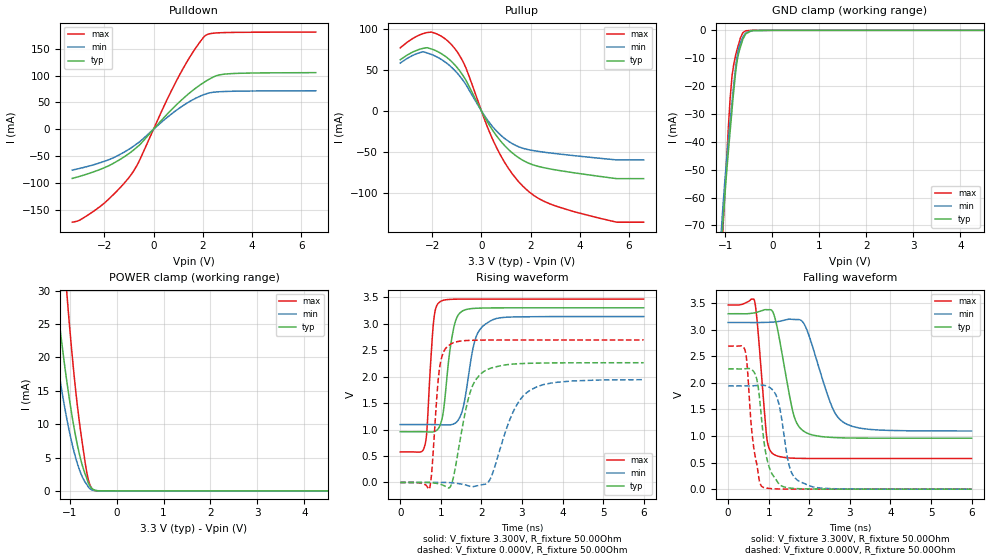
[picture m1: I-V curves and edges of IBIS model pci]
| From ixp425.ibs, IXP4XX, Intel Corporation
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[Model]   pci
Model_type   I/O
Vinl = 800.000mV
Vinh = 2.000V
Vmeas = 1.500V
Cref = 0.000F
|   typ   min   max
C_comp   3.000pF   2.700pF   3.300pF
[Voltage Range]   3.300V   3.135V   3.465V
[Temperature Range]   25.0   110.0   -40.0
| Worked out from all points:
|   slope of the pulldown table from 0 to 0.495 V, typ, clamps not added: 19.6 ohm
|   slope of the pullup table from 0 to 0.495 V, typ, clamps not added: 19.5 ohm
|   GND clamp passes 1 mA (typ) near -0.54 V on its own axis
|   POWER clamp passes 1 mA (typ) near -0.59 V on its own axis
|   falling waveform, V_fixture 3.300V, R_fixture 50.00Ohm: 20-80 % time 343ps typ, 524ps min, 182ps max; typ from 3.3 V to 0.958 V
|   rising waveform, V_fixture 3.300V, R_fixture 50.00Ohm: 20-80 % time 219ps typ, 284ps min, 133ps max; typ from 0.958 V to 3.3 V
|   rising waveform, V_fixture 0.000V, R_fixture 50.00Ohm: 20-80 % time 376ps typ, 580ps min, 158ps max; typ from 0 V to 2.26 V
|   falling waveform, V_fixture 0.000V, R_fixture 50.00Ohm: 20-80 % time 237ps typ, 262ps min, 202ps max; typ from 2.26 V to 0 V
[Pulldown]
|   Voltage   I(typ)   I(min)   I(max)
-3.3V     -91.81mA   -76.25mA   -173.6mA
-2.995V   -87.89mA   -73.11mA   -169.6mA
-2V       -71.83mA   -59.94mA   -138.1mA
-900mV    -42.1mA    -34.42mA   -84.13mA
-600mV    -30.71mA   -24.64mA   -61.1mA
370mV     19.06mA    15.05mA    37.7mA
1.045V    50.61mA    39.26mA    100.2mA
1.59V     72.39mA    54.94mA    143.1mA
2.08V     88.46mA    65.23mA    174mA
2.545V    99.84mA    69.65mA    179.9mA
2.89V     103mA      70.56mA    180.6mA
6.595V    105.8mA    71.9mA     181.5mA
[GND Clamp]
|   Voltage   I(typ)   I(min)   I(max)
-3.3V     -1.837A    -1.782A    -2.142A
-1.1V     -82.16mA   -75.28mA   -89.43mA
-1.06V    -71.18mA   -65.17mA   -74.61mA
-1.045V   -67.36mA   -61.57mA   -69.22mA
-930mV    -42.2mA    -38.29mA   -33.02mA
-860mV    -28.79mA   -26.06mA   -16.73mA
-785mV    -15.48mA   -13.65mA   -9.2mA
-745mV    -10.52mA   -8.798mA   -6.545mA
-680mV    -6.029mA   -4.579mA   -2.739mA
-575mV    -1.514mA   -1.11mA    -221.4uA
0V        -56.89nA   -17.57nA   -32.79pA
6.595V    0A         0A         0A
[Pullup]
|   Voltage   I(typ)   I(min)   I(max)
-3.3V     62.29mA    58.22mA    76.79mA
-2.46V    75.48mA    71.27mA    93.15mA
-2.035V   75.44mA    68.76mA    95.98mA
-1.185V   59.23mA    52.26mA    79.63mA
-670mV    39.32mA    33.81mA    55mA
235mV     -13mA      -10.7mA    -18.96mA
790mV     -37.09mA   -29.71mA   -54.75mA
1.41V     -54.88mA   -42.36mA   -82.66mA
2.11V     -65.9mA    -48.4mA    -102.6mA
3.045V    -72.1mA    -52.2mA    -116.2mA
4.7V      -79.4mA    -57.42mA   -130mA
6.595V    -82.58mA   -59.77mA   -135.6mA
[POWER Clamp]
|   Voltage   I(typ)   I(min)   I(max)
-3.3V     221.1mA    178.3mA    345.2mA
-1.46V    41.39mA    29.65mA    71.72mA
-1.43V    39.23mA    27.98mA    68.17mA
-1.325V   32.02mA    22.46mA    56.21mA
-1.26V    27.84mA    19.29mA    49.19mA
-1.06V    16.51mA    10.87mA    29.8mA
-895mV    9.118mA    5.612mA    16.77mA
-785mV    5.35mA     3.076mA    10.01mA
-635mV    1.89mA     986.6uA    2.845mA
-535mV    440.6uA    188.8uA    455.2uA
-390mV    28.44uA    11.22uA    8.083uA
6.595V    0A         0A         0A
[Ramp]
R_load = 50.00Ohm
|   typ   min   max
dV/dt_r   1.357V/375.181ps   1.165V/579.390ps   1.615V/158.446ps
dV/dt_f   1.405V/342.580ps   1.225V/523.955ps   1.733V/181.950ps
[Falling Waveform]
V_fixture = 3.300V
V_fixture_min = 3.135V
V_fixture_max = 3.465V
R_fixture = 50.00Ohm
|   Time   V(typ)   V(min)   V(max)
0s        3.3V       3.135V     3.465V
650ps     3.317V     3.134V     3.542V
720ps     3.331V     3.134V     3.114V
950ps     3.376V     3.138V     982.6mV
1.13ns    3.279V     3.144V     651.8mV
1.61ns    1.411V     3.193V     582.4mV
1.89ns    1.077V     3.082V     578.1mV
2.54ns    974.4mV    1.586V     576.7mV
2.83ns    964.9mV    1.264V     576.6mV
6ns       958.5mV    1.094V     576.5mV
[Rising Waveform]
V_fixture = 3.300V
V_fixture_min = 3.135V
V_fixture_max = 3.465V
R_fixture = 50.00Ohm
|   Time   V(typ)   V(min)   V(max)
0s        958.5mV    1.094V     576.5mV
610ps     956.7mV    1.094V     709mV
660ps     955.2mV    1.095V     1.011V
820ps     957.2mV    1.094V     3.023V
990ps     1.099V     1.09V      3.42V
1.31ns    2.889V     1.103V     3.461V
1.53ns    3.237V     1.357V     3.464V
1.86ns    3.291V     2.73V      3.465V
2.28ns    3.298V     3.075V     3.465V
6ns       3.3V       3.135V     3.465V
[Rising Waveform]
V_fixture = 0.000V
V_fixture_min = 0.000V
V_fixture_max = 0.000V
R_fixture = 50.00Ohm
|   Time   V(typ)   V(min)   V(max)
0s        782.3nV    285.7nV    1.747nV
720ps     -976.7uV   178.1uV    -115mV
970ps     -29.9mV    773.6uV    2.168V
1.25ns    -59.19mV   -5.463mV   2.617V
1.69ns    1.615V     -66.83mV   2.684V
2.06ns    2.097V     -37.48mV   2.69V
2.26ns    2.166V     140.6mV    2.691V
2.78ns    2.236V     1.328V     2.692V
3.18ns    2.251V     1.73V      2.692V
6ns       2.262V     1.942V     2.692V
[Falling Waveform]
V_fixture = 0.000V
V_fixture_min = 0.000V
V_fixture_max = 0.000V
R_fixture = 50.00Ohm
|   Time   V(typ)   V(min)   V(max)
0s        2.262V     1.942V     2.692V
420ps     2.265V     1.942V     2.6V
620ps     2.221V     1.944V     841.9mV
730ps     1.972V     1.952V     354.2mV
850ps     1.118V     1.956V     40.47mV
1.08ns    288.5mV    1.879V     8.799mV
1.26ns    94.52mV    1.569V     3.397mV
1.51ns    22.88mV    427.2mV    1.167mV
1.77ns    8.151mV    140mV      481.7uV
6ns       782.3nV    285.7nV    1.747nV
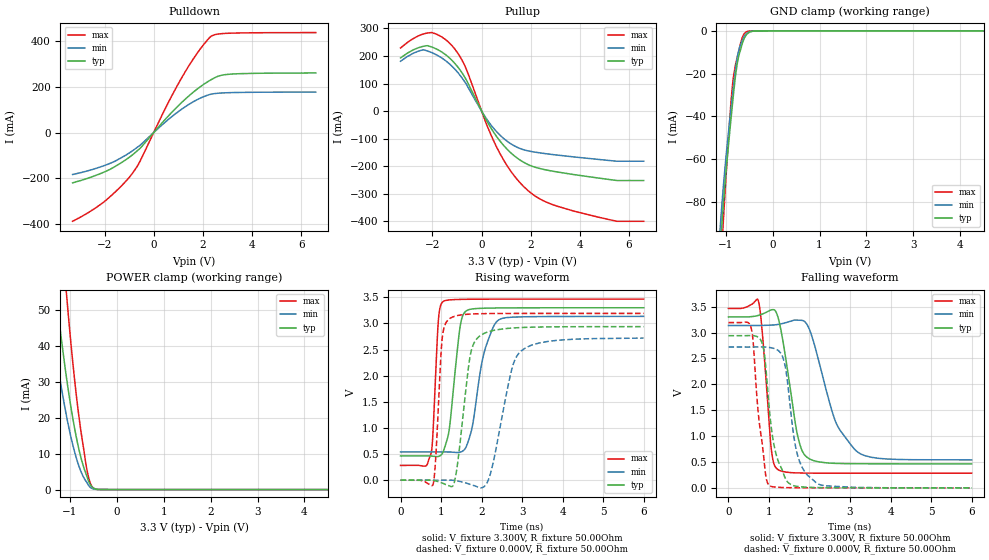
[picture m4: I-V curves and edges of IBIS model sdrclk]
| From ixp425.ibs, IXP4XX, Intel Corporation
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[Model]   sdrclk
Model_type   I/O
Vinl = 800.000mV
Vinh = 2.000V
Vmeas = 1.500V
Cref = 0.000F
|   typ   min   max
C_comp   3.000pF   2.700pF   3.300pF
[Voltage Range]   3.300V   3.135V   3.465V
[Temperature Range]   25.0   110.0   -40.0
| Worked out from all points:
|   slope of the pulldown table from 0 to 0.495 V, typ, clamps not added: 8.2 ohm
|   slope of the pullup table from 0 to 0.495 V, typ, clamps not added: 6.39 ohm
|   GND clamp passes 1 mA (typ) near -0.51 V on its own axis
|   POWER clamp passes 1 mA (typ) near -0.54 V on its own axis
|   falling waveform, V_fixture 3.300V, R_fixture 50.00Ohm: 20-80 % time 335ps typ, 631ps min, 182ps max; typ from 3.3 V to 0.464 V
|   rising waveform, V_fixture 3.300V, R_fixture 50.00Ohm: 20-80 % time 224ps typ, 353ps min, 114ps max; typ from 0.464 V to 3.3 V
|   rising waveform, V_fixture 0.000V, R_fixture 50.00Ohm: 20-80 % time 262ps typ, 422ps min, 126ps max; typ from 0 V to 2.94 V
|   falling waveform, V_fixture 0.000V, R_fixture 50.00Ohm: 20-80 % time 279ps typ, 304ps min, 231ps max; typ from 2.94 V to 0 V
[Pulldown]
|   Voltage   I(typ)   I(min)   I(max)
-3.3V     -219mA     -182.8mA   -386.5mA
-2.07V    -174.3mA   -146.1mA   -305.9mA
-1.35V    -133.5mA   -111.6mA   -236.4mA
-865mV    -97.09mA   -79.63mA   -177.4mA
-590mV    -72.25mA   -58.19mA   -131.8mA
495mV     60.39mA    47.75mA    109.6mA
1.11V     128.1mA    99.6mA     233.2mA
1.73V     186.1mA    141.1mA    339.5mA
2.3V      228mA      166.3mA    416.3mA
2.645V    246.3mA    171.5mA    429.5mA
3.12V     254.4mA    173.9mA    432.9mA
6.595V    259.6mA    176.5mA    435.6mA
[GND Clamp]
|   Voltage   I(typ)   I(min)   I(max)
-3.3V     -1.926A    -1.857A    -2.229A
-1.11V    -99.68mA   -89.97mA   -113.7mA
-1.065V   -85.71mA   -77.06mA   -94.89mA
-1.045V   -79.88mA   -71.62mA   -87.17mA
-890mV    -42.05mA   -37.16mA   -34.22mA
-840mV    -31.08mA   -27.22mA   -22.58mA
-785mV    -20.1mA    -17.16mA   -15.29mA
-740mV    -13.67mA   -10.94mA   -11.14mA
-645mV    -5.889mA   -4.486mA   -3.1mA
-550mV    -1.607mA   -1.138mA   -370.4uA
0V        -99.35nA   -30.05nA   -3.864nA
6.595V    0A         0A         0A
[Pullup]
|   Voltage   I(typ)   I(min)   I(max)
-3.3V     193mA      180.8mA    229.1mA
-2.47V    232.9mA    220.3mA    276.8mA
-2.035V   232.7mA    212.5mA    285mA
-1.185V   182.2mA    161mA      235.4mA
-685mV    123mA      106mA      164.9mA
240mV     -40.44mA   -33.33mA   -56.56mA
795mV     -113.9mA   -91.35mA   -161.8mA
1.415V    -168.4mA   -130mA     -244.7mA
2.12V     -202.3mA   -148.3mA   -304.8mA
3.035V    -220.4mA   -159.3mA   -344.1mA
4.69V     -242.3mA   -174.9mA   -383.7mA
6.595V    -252mA     -182.1mA   -400.1mA
[POWER Clamp]
|   Voltage   I(typ)   I(min)   I(max)
-3.3V     403.8mA    324.6mA    607.2mA
-1.51V    81.8mA     58.73mA    136mA
-1.45V    73.79mA    52.55mA    123.4mA
-1.275V   52.29mA    36.16mA    89.09mA
-1.095V   33.38mA    22.11mA    58.17mA
-1.06V    30.12mA    19.74mA    52.74mA
-920mV    18.6mA     11.56mA    33.24mA
-770mV    9.234mA    5.265mA    16.86mA
-635mV    3.649mA    1.937mA    5.465mA
-530mV    782.2uA    338.8uA    898uA
-390mV    54.09uA    21.66uA    23.63uA
6.595V    0A         0A         0A
[Ramp]
R_load = 50.00Ohm
|   typ   min   max
dV/dt_r   1.763V/261.419ps   1.632V/421.770ps   1.915V/125.723ps
dV/dt_f   1.702V/333.826ps   1.557V/629.863ps   1.909V/181.980ps
[Falling Waveform]
V_fixture = 3.300V
V_fixture_min = 3.135V
V_fixture_max = 3.465V
R_fixture = 50.00Ohm
|   Time   V(typ)   V(min)   V(max)
0s        3.3V       3.135V     3.465V
740ps     3.331V     3.135V     3.607V
840ps     3.358V     3.136V     2.961V
1.06ns    3.437V     3.143V     731.4mV
1.22ns    3.302V     3.155V     354.6mV
1.71ns    996.4mV    3.238V     288.5mV
1.95ns    584.5mV    3.141V     284.8mV
2.65ns    472.7mV    1.266V     283mV
3.15ns    466mV      716.6mV    283mV
6ns       463.8mV    540.5mV    283mV
[Rising Waveform]
V_fixture = 3.300V
V_fixture_min = 3.135V
V_fixture_max = 3.465V
R_fixture = 50.00Ohm
|   Time   V(typ)   V(min)   V(max)
0s        463.8mV    540.5mV    283mV
750ps     463.2mV    540.7mV    504.2mV
940ps     455.9mV    541.2mV    3.11V
1.06ns    560mV      541mV      3.423V
1.21ns    1.017V     539.5mV    3.45V
1.47ns    2.936V     536.4mV    3.46V
1.63ns    3.244V     657.4mV    3.462V
2.04ns    3.291V     2.37V      3.464V
2.4ns     3.296V     3.054V     3.465V
6ns       3.3V       3.135V     3.465V
[Rising Waveform]
V_fixture = 0.000V
V_fixture_min = 0.000V
V_fixture_max = 0.000V
R_fixture = 50.00Ohm
|   Time   V(typ)   V(min)   V(max)
0s        681.1nV    252.1nV    17.49nV
810ps     -4.265mV   -82.87uV   -61.55mV
1.02ns    -52.01mV   686.6uV    2.649V
1.21ns    -110.1mV   1.425mV    3.091V
1.38ns    167.3mV    -10.78mV   3.146V
1.72ns    2.385V     -81.1mV    3.179V
1.94ns    2.75V      -143.6mV   3.186V
2.22ns    2.852V     128.8mV    3.189V
2.97ns    2.921V     2.468V     3.191V
6ns       2.939V     2.72V      3.192V
[Falling Waveform]
V_fixture = 0.000V
V_fixture_min = 0.000V
V_fixture_max = 0.000V
R_fixture = 50.00Ohm
|   Time   V(typ)   V(min)   V(max)
0s        2.939V     2.72V      3.192V
560ps     2.942V     2.72V      3.088V
740ps     2.906V     2.721V     1.415V
860ps     2.71V      2.721V     677.5mV
1.02ns    1.429V     2.71V      39.61mV
1.17ns    668.4mV    2.678V     14.38mV
1.44ns    132.5mV    2.153V     5.135mV
1.71ns    26.59mV    618.7mV    1.425mV
2.2ns     5.963mV    81.25mV    119.6uV
6ns       681.1nV    252.1nV    17.49nV
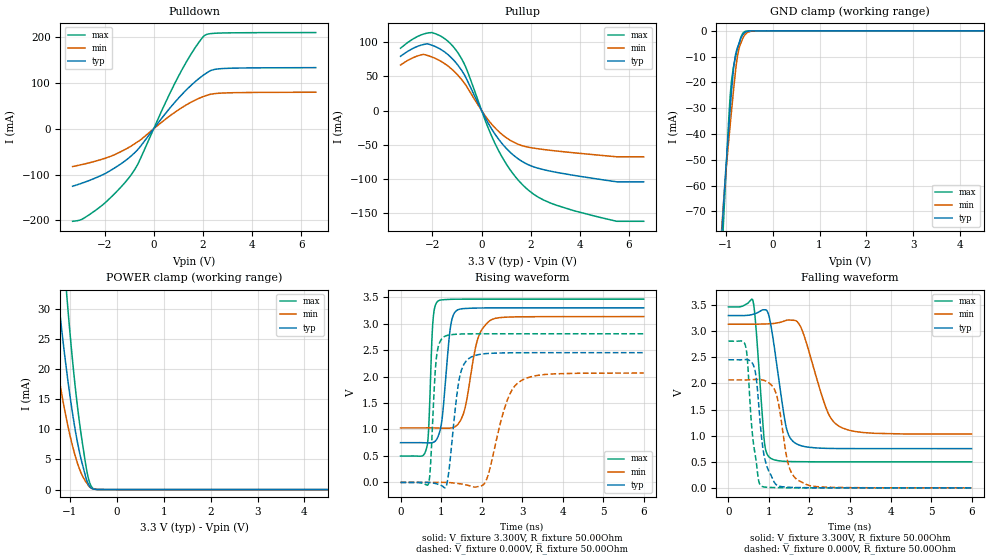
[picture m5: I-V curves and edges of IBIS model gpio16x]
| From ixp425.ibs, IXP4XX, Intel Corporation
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[Model]   gpio16x
Model_type   I/O
Vinl = 800.000mV
Vinh = 2.000V
Vmeas = 1.500V
Cref = 0.000F
|   typ   min   max
C_comp   3.000pF   2.700pF   3.300pF
[Voltage Range]   3.300V   3.135V   3.465V
[Temperature Range]   25.0   110.0   -40.0
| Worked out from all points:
|   slope of the pulldown table from 0 to 0.495 V, typ, clamps not added: 14.4 ohm
|   slope of the pullup table from 0 to 0.495 V, typ, clamps not added: 15.5 ohm
|   GND clamp passes 1 mA (typ) near -0.61 V on its own axis
|   POWER clamp passes 1 mA (typ) near -0.61 V on its own axis
|   falling waveform, V_fixture 3.300V, R_fixture 50.00Ohm: 20-80 % time 285ps typ, 501ps min, 165ps max; typ from 3.3 V to 0.751 V
|   rising waveform, V_fixture 3.300V, R_fixture 50.00Ohm: 20-80 % time 174ps typ, 302ps min, 86.6ps max; typ from 0.751 V to 3.3 V
|   rising waveform, V_fixture 0.000V, R_fixture 50.00Ohm: 20-80 % time 218ps typ, 436ps min, 114ps max; typ from 0 V to 2.45 V
|   falling waveform, V_fixture 0.000V, R_fixture 50.00Ohm: 20-80 % time 213ps typ, 266ps min, 188ps max; typ from 2.45 V to 0 V
[Pulldown]
|   Voltage   I(typ)   I(min)   I(max)
-3.3V     -125.4mA   -82.36mA   -201.8mA
-2.93V    -118.8mA   -78.18mA   -197.8mA
-2.115V   -101.3mA   -66.61mA   -167.7mA
-1.45V    -80.63mA   -52.89mA   -133.9mA
-895mV    -58.28mA   -36.91mA   -98.77mA
-595mV    -42.09mA   -26.41mA   -71.46mA
980mV     65.04mA    40.31mA    111.7mA
1.57V     97.14mA    59.35mA    167.2mA
2.065V    118.6mA    71.18mA    203.4mA
2.345V    127.5mA    75.58mA    207.8mA
2.805V    131.4mA    77.96mA    209mA
6.595V    133.4mA    79.74mA    209.9mA
[GND Clamp]
|   Voltage   I(typ)   I(min)   I(max)
-3.3V     -1.979A    -1.804A    -2.212A
-1.08V    -77.96mA   -75.5mA    -87.33mA
-1.065V   -73.1mA    -71.52mA   -81.39mA
-1.04V    -65.73mA   -65.17mA   -71.73mA
-940mV    -39.12mA   -43.51mA   -36.09mA
-910mV    -31.62mA   -37.69mA   -26.87mA
-875mV    -23.18mA   -31.01mA   -19.34mA
-825mV    -13.43mA   -21.63mA   -13.19mA
-745mV    -6.328mA   -9.483mA   -6.815mA
-600mV    -790.9uA   -1.771mA   -361.3uA
0V        -2.614nA   -17.07nA   633.7pA
6.595V    0A         0A         0A
[Pullup]
|   Voltage   I(typ)   I(min)   I(max)
-3.3V     79.48mA    66.76mA    91.32mA
-2.48V    95.65mA    81.38mA    110.5mA
-2.035V   95.89mA    78.63mA    114.2mA
-1.16V    74.74mA    58.82mA    93.84mA
-630mV    47.44mA    36.5mA     62.19mA
215mV     -15.07mA   -11.19mA   -20.82mA
725mV     -43.56mA   -31.71mA   -60.99mA
1.4V      -68.41mA   -48.02mA   -98.13mA
2.105V    -82.35mA   -54.99mA   -122.2mA
3.04V     -90.52mA   -59.25mA   -138.7mA
4.67V     -100.1mA   -65.02mA   -155.2mA
6.595V    -104.4mA   -67.76mA   -162.3mA
[POWER Clamp]
|   Voltage   I(typ)   I(min)   I(max)
-3.3V     262.4mA    183.1mA    371.6mA
-1.5V     52.41mA    32.82mA    81.89mA
-1.47V    49.77mA    31.06mA    77.98mA
-1.365V   40.92mA    25.22mA    64.82mA
-1.25V    31.99mA    19.39mA    51.36mA
-1.065V   19.49mA    11.44mA    32.16mA
-905mV    10.81mA    6.129mA    18.51mA
-780mV    5.701mA    3.138mA    10.3mA
-630mV    1.332mA    997.1uA    2.762mA
-575mV    505uA      414.6uA    1.093mA
-515mV    136.2uA    138.7uA    252.7uA
6.595V    0A         0A         0A
[Ramp]
R_load = 50.00Ohm
|   typ   min   max
dV/dt_r   1.472V/218.343ps   1.241V/435.688ps   1.686V/114.468ps
dV/dt_f   1.530V/284.916ps   1.263V/500.627ps   1.780V/164.693ps
[Falling Waveform]
V_fixture = 3.300V
V_fixture_min = 3.135V
V_fixture_max = 3.465V
R_fixture = 50.00Ohm
|   Time   V(typ)   V(min)   V(max)
0s        3.3V       3.135V     3.465V
600ps     3.322V     3.134V     3.595V
670ps     3.34V      3.134V     3.157V
890ps     3.411V     3.139V     864.4mV
1.04ns    3.147V     3.143V     568mV
1.42ns    1.179V     3.206V     506.7mV
1.67ns    847.4mV    3.198V     501.7mV
2.44ns    756.3mV    1.468V     498.8mV
2.69ns    753.3mV    1.201V     498.7mV
6ns       750.8mV    1.03V      498.7mV
[Rising Waveform]
V_fixture = 3.300V
V_fixture_min = 3.135V
V_fixture_max = 3.465V
R_fixture = 50.00Ohm
|   Time   V(typ)   V(min)   V(max)
0s        750.8mV    1.03V      498.7mV
650ps     747.3mV    1.031V     668.3mV
700ps     746.3mV    1.031V     1.109V
800ps     755mV      1.03V      3.048V
930ps     874.7mV    1.028V     3.431V
1.23ns    2.923V     1.027V     3.461V
1.39ns    3.252V     1.078V     3.464V
1.91ns    3.297V     2.722V     3.465V
2.21ns    3.299V     3.061V     3.465V
6ns       3.3V       3.135V     3.465V
[Rising Waveform]
V_fixture = 0.000V
V_fixture_min = 0.000V
V_fixture_max = 0.000V
R_fixture = 50.00Ohm
|   Time   V(typ)   V(min)   V(max)
0s        30.73nV    264nV      -2.874nV
690ps     -2.002mV   173.4uV    -27.4mV
880ps     -24.43mV   831.2uV    2.318V
1.08ns    -99.23mV   -178.2uV   2.756V
1.45ns    1.957V     -24.42mV   2.804V
1.69ns    2.344V     -61.09mV   2.808V
2.11ns    2.435V     29.15mV    2.81V
2.6ns     2.449V     1.479V     2.81V
2.99ns    2.452V     1.929V     2.81V
6ns       2.453V     2.068V     2.81V
[Falling Waveform]
V_fixture = 0.000V
V_fixture_min = 0.000V
V_fixture_max = 0.000V
R_fixture = 50.00Ohm
|   Time   V(typ)   V(min)   V(max)
0s        2.453V     2.068V     2.81V
430ps     2.458V     2.067V     2.69V
570ps     2.409V     2.072V     1.21V
660ps     2.231V     2.076V     635.5mV
810ps     1.021V     2.071V     35.17mV
930ps     458.5mV    2.042V     12.5mV
1.15ns    85.1mV     1.86V      5.128mV
1.5ns     11.47mV    392mV      1.284mV
1.91ns    3.597mV    68.26mV    156uV
6ns       30.73nV    264nV      -2.874nV
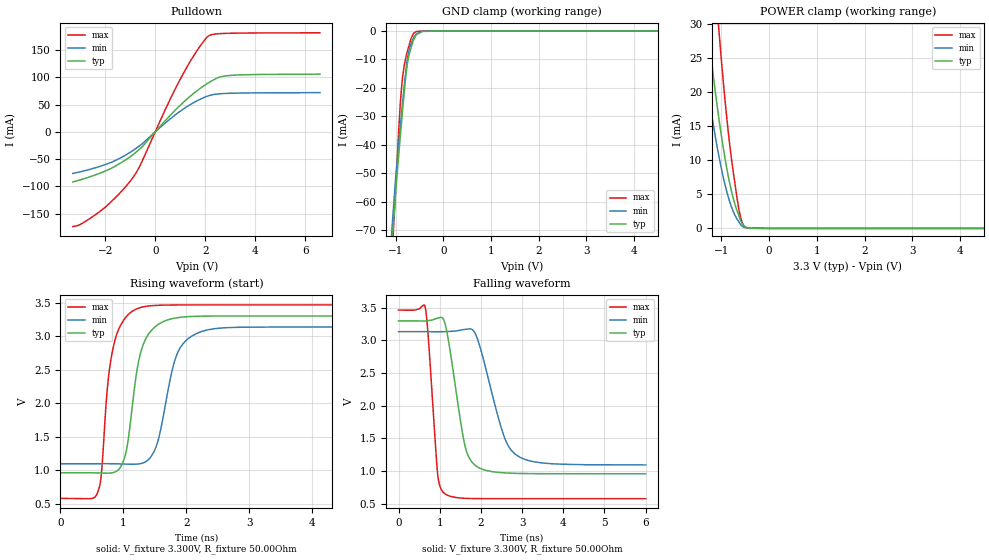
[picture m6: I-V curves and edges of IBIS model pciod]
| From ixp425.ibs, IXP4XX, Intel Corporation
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[Model]   pciod
Model_type   I/O_open_drain
Vinl = 800.000mV
Vinh = 2.000V
Vmeas = 1.500V
Cref = 0.000F
|   typ   min   max
C_comp   3.000pF   2.700pF   3.300pF
[Voltage Range]   3.300V   3.135V   3.465V
[Temperature Range]   25.0   110.0   -40.0
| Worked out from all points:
|   slope of the pulldown table from 0 to 0.495 V, typ, clamps not added: 19.7 ohm
|   GND clamp passes 1 mA (typ) near -0.54 V on its own axis
|   POWER clamp passes 1 mA (typ) near -0.59 V on its own axis
|   falling waveform, V_fixture 3.300V, R_fixture 50.00Ohm: 20-80 % time 344ps typ, 525ps min, 183ps max; typ from 3.3 V to 0.958 V
|   rising waveform, V_fixture 3.300V, R_fixture 50.00Ohm: 20-80 % time 228ps typ, 284ps min, 184ps max; typ from 0.958 V to 3.3 V
[Pulldown]
|   Voltage   I(typ)   I(min)   I(max)
-3.3V     -91.81mA   -76.25mA   -173.6mA
-2.995V   -87.89mA   -73.11mA   -169.6mA
-2V       -71.83mA   -59.94mA   -138.1mA
-890mV    -41.74mA   -34.11mA   -83.49mA
-600mV    -30.71mA   -24.64mA   -61.1mA
370mV     19.06mA    15.05mA    37.7mA
1.045V    50.61mA    39.26mA    100.2mA
1.59V     72.39mA    54.94mA    143.1mA
2.08V     88.46mA    65.23mA    174mA
2.545V    99.84mA    69.65mA    179.9mA
2.89V     103mA      70.56mA    180.6mA
6.595V    105.8mA    71.9mA     181.5mA
[GND Clamp]
|   Voltage   I(typ)   I(min)   I(max)
-3.3V     -1.837A    -1.782A    -2.142A
-1.11V    -84.99mA   -78.1mA    -93.33mA
-1.075V   -75.12mA   -68.77mA   -79.91mA
-1.05V    -68.6mA    -62.87mA   -70.92mA
-905mV    -37.35mA   -33.82mA   -26.01mA
-860mV    -28.79mA   -26.1mA    -16.73mA
-785mV    -15.48mA   -13.66mA   -9.203mA
-745mV    -10.52mA   -8.794mA   -6.562mA
-680mV    -6.029mA   -4.581mA   -2.725mA
-575mV    -1.514mA   -1.109mA   -221.4uA
0V        -56.89nA   -17.57nA   -32.79pA
6.595V    0A         0A         0A
[POWER Clamp]
|   Voltage   I(typ)   I(min)   I(max)
-3.3V     221.1mA    178.3mA    345.2mA
-1.495V   43.96mA    31.64mA    75.93mA
-1.43V    39.23mA    27.99mA    68.17mA
-1.32V    31.69mA    22.21mA    55.65mA
-1.26V    27.84mA    19.29mA    49.19mA
-1.06V    16.51mA    10.87mA    29.8mA
-1.045V   15.76mA    10.32mA    28.5mA
-905mV    9.508mA    5.882mA    17.46mA
-795mV    5.65mA     3.273mA    10.55mA
-635mV    1.89mA     986.6uA    2.845mA
-535mV    440.6uA    188.8uA    455.2uA
6.595V    0A         0A         0A
[Ramp]
R_load = 50.00Ohm
|   typ   min   max
dV/dt_r   1.297uV/16.690ps  419.205nV/17.191ps   56.118nV/4.826ps
dV/dt_f   1.405V/343.196ps   1.225V/524.342ps   1.733V/182.577ps
[Falling Waveform]
V_fixture = 3.300V
V_fixture_min = 3.135V
V_fixture_max = 3.465V
R_fixture = 50.00Ohm
|   Time   V(typ)   V(min)   V(max)
0s        3.3V       3.135V     3.465V
650ps     3.3V       3.135V     3.505V
720ps     3.304V     3.135V     3.071V
950ps     3.342V     3.134V     956.8mV
1.12ns    3.278V     3.135V     654.6mV
1.59ns    1.453V     3.168V     582.9mV
1.87ns    1.084V     3.095V     578.2mV
2.53ns    974.6mV    1.591V     576.7mV
2.82ns    965mV      1.266V     576.6mV
6ns       958.5mV    1.094V     576.5mV
[Rising Waveform]
V_fixture = 3.300V
V_fixture_min = 3.135V
V_fixture_max = 3.465V
R_fixture = 50.00Ohm
|   Time   V(typ)   V(min)   V(max)
0s        958.5mV    1.094V     576.5mV
590ps     957.1mV    1.094V     662.7mV
650ps     955.4mV    1.095V     937.9mV
830ps     959.8mV    1.094V     2.792V
1.03ns    1.22V      1.089V     3.271V
1.18ns    2.254V     1.087V     3.392V
1.45ns    3.09V      1.215V     3.453V
1.85ns    3.273V     2.724V     3.464V
2.16ns    3.295V     3.037V     3.465V
6ns       3.3V       3.135V     3.465V
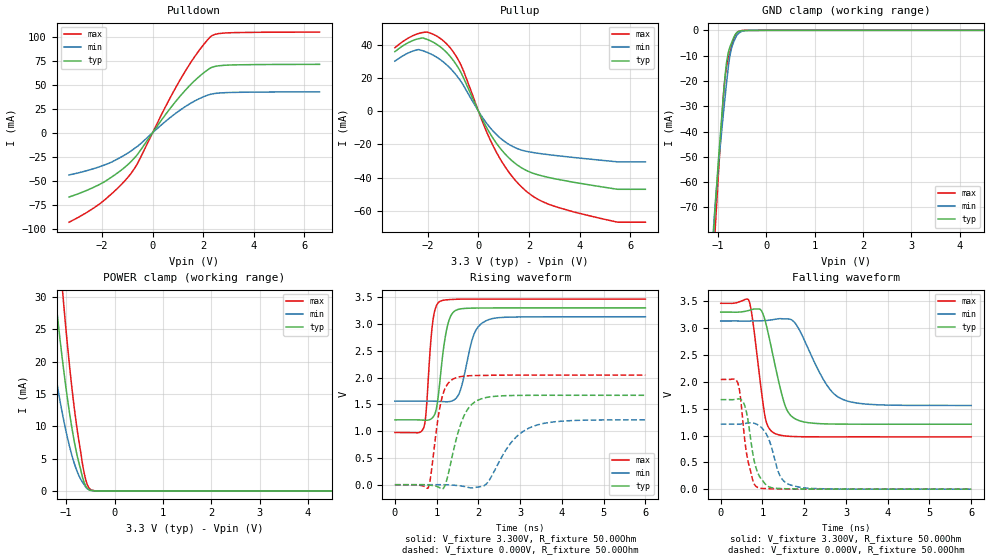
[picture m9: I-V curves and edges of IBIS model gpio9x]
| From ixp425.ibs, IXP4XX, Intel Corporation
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[Model]   gpio9x
Model_type   I/O
Vinl = 800.000mV
Vinh = 2.000V
Vmeas = 1.500V
Cref = 0.000F
|   typ   min   max
C_comp   3.000pF   2.700pF   3.300pF
[Voltage Range]   3.300V   3.135V   3.465V
[Temperature Range]   25.0   110.0   -40.0
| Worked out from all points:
|   slope of the pulldown table from 0 to 0.495 V, typ, clamps not added: 27 ohm
|   slope of the pullup table from 0 to 0.495 V, typ, clamps not added: 34.5 ohm
|   GND clamp passes 1 mA (typ) near -0.61 V on its own axis
|   POWER clamp passes 1 mA (typ) near -0.61 V on its own axis
|   falling waveform, V_fixture 3.300V, R_fixture 50.00Ohm: 20-80 % time 368ps typ, 624ps min, 240ps max; typ from 3.3 V to 1.21 V
|   rising waveform, V_fixture 3.300V, R_fixture 50.00Ohm: 20-80 % time 201ps typ, 292ps min, 137ps max; typ from 1.21 V to 3.3 V
|   rising waveform, V_fixture 0.000V, R_fixture 50.00Ohm: 20-80 % time 370ps typ, 651ps min, 232ps max; typ from 0 V to 1.67 V
|   falling waveform, V_fixture 0.000V, R_fixture 50.00Ohm: 20-80 % time 232ps typ, 295ps min, 205ps max; typ from 1.67 V to 0 V
[Pulldown]
|   Voltage   I(typ)   I(min)   I(max)
-3.3V     -66.86mA   -43.92mA   -93.01mA
-2.05V    -53.11mA   -34.94mA   -73.21mA
-1.335V   -40.81mA   -26.61mA   -56.53mA
-855mV    -30.03mA   -18.98mA   -42.35mA
-580mV    -21.93mA   -13.78mA   -31.15mA
510mV     18.88mA    11.8mA     27.08mA
1.11V     38.74mA    23.95mA    56.02mA
1.73V     55.83mA    33.94mA    81.64mA
2.3V      67.48mA    40.04mA    100.1mA
2.6V      69.58mA    41.22mA    103mA
3.115V    70.46mA    41.89mA    104mA
6.595V    71.12mA    42.53mA    104.7mA
[GND Clamp]
|   Voltage   I(typ)   I(min)   I(max)
-3.3V     -1.979A    -1.804A    -2.12A
-1.085V   -79.48mA   -76.86mA   -89.43mA
-1.08V    -77.76mA   -75.39mA   -87.63mA
-1.05V    -68.57mA   -67.57mA   -76.8mA
-995mV    -53.23mA   -54.78mA   -58.88mA
-900mV    -29.27mA   -35.8mA    -29.82mA
-850mV    -17.85mA   -26.31mA   -18.42mA
-790mV    -9.296mA   -15.53mA   -11.43mA
-740mV    -6.079mA   -8.954mA   -7.873mA
-670mV    -2.681mA   -4.492mA   -3.297mA
-570mV    -429.5uA   -1.119mA   -393.9uA
6.595V    0A         0A         0A
[Pullup]
|   Voltage   I(typ)   I(min)   I(max)
-3.3V     35.77mA    30.04mA    38.14mA
-2.585V   42.46mA    36.12mA    45.38mA
-2.2V     43.98mA    36.3mA     47.26mA
-1.255V   35.19mA    27.84mA    40.42mA
-700mV    23.53mA    18.01mA    28.03mA
190mV     -6.038mA   -4.489mA   -7.592mA
700mV     -19.07mA   -13.9mA    -24.41mA
1.4V      -30.79mA   -21.61mA   -40.57mA
2.11V     -37.08mA   -24.76mA   -50.71mA
3.045V    -40.75mA   -26.67mA   -57.42mA
4.75V     -45.23mA   -29.38mA   -64.23mA
6.595V    -46.99mA   -30.49mA   -66.76mA
[POWER Clamp]
|   Voltage   I(typ)   I(min)   I(max)
-3.3V     262.4mA    183.1mA    340.6mA
-1.5V     52.41mA    32.82mA    75.43mA
-1.435V   46.75mA    29.06mA    67.79mA
-1.24V    31.26mA    18.92mA    46.56mA
-1.195V   28.02mA    16.84mA    42.06mA
-1.08V    20.41mA    12.01mA    31.35mA
-1.06V    19.18mA    11.25mA    29.61mA
-930mV    12.02mA    6.853mA    19.28mA
-780mV    5.702mA    3.138mA    9.872mA
-630mV    1.332mA    997.1uA    2.826mA
-515mV    136.2uA    138.7uA    344.2uA
6.595V    0A         0A         0A
[Ramp]
R_load = 50.00Ohm
|   typ   min   max
dV/dt_r   1.001V/369.989ps 727.140mV/650.170ps   1.228V/231.956ps
dV/dt_f   1.254V/367.680ps 945.049mV/623.151ps   1.494V/239.455ps
[Falling Waveform]
V_fixture = 3.300V
V_fixture_min = 3.135V
V_fixture_max = 3.465V
R_fixture = 50.00Ohm
|   Time   V(typ)   V(min)   V(max)
0s        3.3V       3.135V     3.465V
680ps     3.333V     3.134V     3.505V
950ps     3.349V     3.139V     1.982V
1.06ns    3.152V     3.143V     1.359V
1.28ns    2.389V     3.164V     1.045V
1.58ns    1.485V     3.173V     989.2mV
1.9ns     1.272V     2.945V     978mV
2.49ns    1.218V     2.004V     975mV
2.92ns    1.212V     1.674V     975.2mV
6ns       1.211V     1.56V      974.6mV
[Rising Waveform]
V_fixture = 3.300V
V_fixture_min = 3.135V
V_fixture_max = 3.465V
R_fixture = 50.00Ohm
|   Time   V(typ)   V(min)   V(max)
0s        1.211V     1.56V      974.6mV
690ps     1.206V     1.561V     1.065V
750ps     1.204V     1.561V     1.383V
900ps     1.249V     1.56V      2.998V
1.08ns    1.944V     1.553V     3.423V
1.26ns    2.969V     1.549V     3.452V
1.49ns    3.265V     1.636V     3.462V
1.9ns     3.297V     2.817V     3.464V
2.2ns     3.299V     3.066V     3.465V
6ns       3.3V       3.135V     3.465V
[Rising Waveform]
V_fixture = 0.000V
V_fixture_min = 0.000V
V_fixture_max = 0.000V
R_fixture = 50.00Ohm
|   Time   V(typ)   V(min)   V(max)
0s        46.68nV    388.3nV    27.08nV
800ps     -5.141mV   207.8uV    -53.21mV
1.12ns    -81.61mV   588.6uV    1.601V
1.24ns    82.15mV    -955.1uV   1.853V
1.43ns    727.3mV    -10.22mV   1.986V
1.72ns    1.38V      -43.09mV   2.031V
2.14ns    1.619V     -17.24mV   2.04V
2.8ns     1.665V     801.5mV    2.045V
3.27ns    1.669V     1.077V     2.046V
6ns       1.669V     1.212V     2.046V
[Falling Waveform]
V_fixture = 0.000V
V_fixture_min = 0.000V
V_fixture_max = 0.000V
R_fixture = 50.00Ohm
|   Time   V(typ)   V(min)   V(max)
0s        1.669V     1.212V     2.046V
410ps     1.682V     1.21V      1.977V
550ps     1.605V     1.221V     1.105V
640ps     1.341V     1.231V     575.6mV
780ps     615.5mV    1.232V     137.7mV
890ps     300.3mV    1.199V     30.55mV
1.13ns    54.08mV    969.4mV    8.283mV
1.43ns    11.69mV    234.9mV    3.305mV
1.66ns    6.134mV    80.87mV    1.179mV
6ns       46.68nV    388.3nV    27.08nV
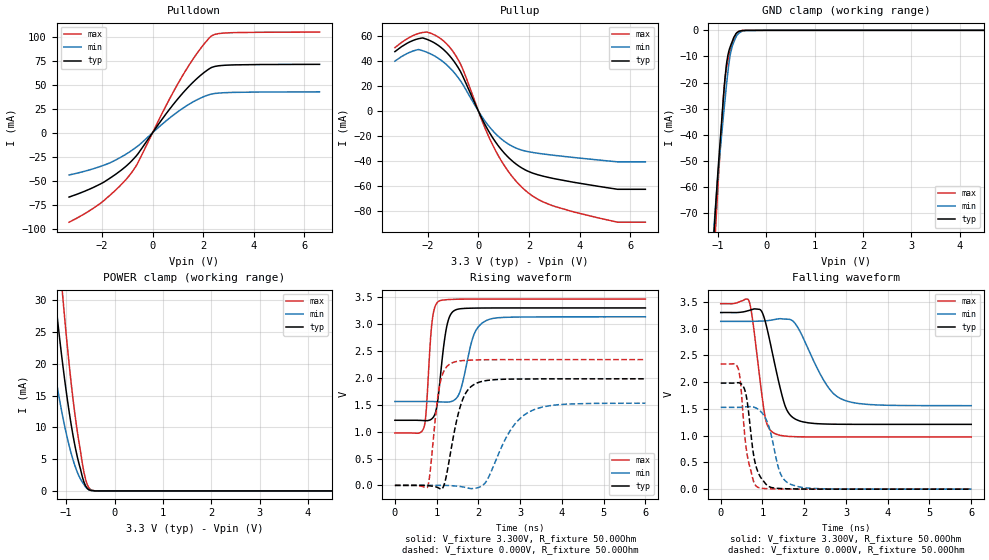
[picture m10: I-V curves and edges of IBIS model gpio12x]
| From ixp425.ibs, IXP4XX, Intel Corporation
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[Model]   gpio12x
Model_type   I/O
Vinl = 800.000mV
Vinh = 2.000V
Vmeas = 1.500V
Cref = 0.000F
|   typ   min   max
C_comp   3.000pF   2.700pF   3.300pF
[Voltage Range]   3.300V   3.135V   3.465V
[Temperature Range]   25.0   110.0   -40.0
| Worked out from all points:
|   slope of the pulldown table from 0 to 0.495 V, typ, clamps not added: 27 ohm
|   slope of the pullup table from 0 to 0.495 V, typ, clamps not added: 25.9 ohm
|   GND clamp passes 1 mA (typ) near -0.61 V on its own axis
|   POWER clamp passes 1 mA (typ) near -0.61 V on its own axis
|   falling waveform, V_fixture 3.300V, R_fixture 50.00Ohm: 20-80 % time 368ps typ, 624ps min, 240ps max; typ from 3.3 V to 1.21 V
|   rising waveform, V_fixture 3.300V, R_fixture 50.00Ohm: 20-80 % time 190ps typ, 292ps min, 122ps max; typ from 1.21 V to 3.3 V
|   rising waveform, V_fixture 0.000V, R_fixture 50.00Ohm: 20-80 % time 332ps typ, 638ps min, 202ps max; typ from 0 V to 1.98 V
|   falling waveform, V_fixture 0.000V, R_fixture 50.00Ohm: 20-80 % time 214ps typ, 293ps min, 191ps max; typ from 1.98 V to 0 V
[Pulldown]
|   Voltage   I(typ)   I(min)   I(max)
-3.3V     -66.86mA   -43.92mA   -93.01mA
-2.065V   -53.33mA   -35.08mA   -73.51mA
-1.295V   -40.01mA   -26.03mA   -55.47mA
-865mV    -30.31mA   -19.15mA   -42.71mA
-575mV    -21.75mA   -13.68mA   -30.9mA
495mV     18.35mA    11.47mA    26.31mA
1.11V     38.74mA    23.95mA    56.02mA
1.73V     55.83mA    33.94mA    81.64mA
2.3V      67.48mA    40.04mA    100.1mA
2.6V      69.58mA    41.22mA    103mA
3.115V    70.46mA    41.89mA    104mA
6.595V    71.12mA    42.53mA    104.7mA
[GND Clamp]
|   Voltage   I(typ)   I(min)   I(max)
-3.3V     -1.979A    -1.804A    -2.12A
-1.095V   -82.68mA   -79.53mA   -93.36mA
-1.075V   -76.18mA   -74.13mA   -85.81mA
-1.055V   -69.97mA   -68.85mA   -78.64mA
-1.005V   -55.85mA   -57.02mA   -62.05mA
-890mV    -26.87mA   -33.83mA   -27.04mA
-850mV    -17.89mA   -26.32mA   -18.43mA
-795mV    -9.779mA   -16.34mA   -11.85mA
-745mV    -6.334mA   -9.471mA   -8.203mA
-670mV    -2.691mA   -4.495mA   -3.306mA
-565mV    -386.8uA   -1.034mA   -348.7uA
6.595V    0A         0A         0A
[Pullup]
|   Voltage   I(typ)   I(min)   I(max)
-3.3V     47.69mA    40.06mA    50.86mA
-2.585V   56.62mA    48.16mA    60.51mA
-2.2V     58.64mA    48.4mA     63.02mA
-1.745V   54.75mA    44.34mA    61.18mA
-1.26V    47.03mA    37.21mA    53.99mA
-700mV    31.38mA    24.02mA    37.37mA
190mV     -8.051mA   -5.985mA   -10.12mA
700mV     -25.43mA   -18.53mA   -32.54mA
1.4V      -41.05mA   -28.81mA   -54.1mA
2.11V     -49.45mA   -33.01mA   -67.62mA
4.685V    -60.1mA    -39.04mA   -85.33mA
6.595V    -62.65mA   -40.66mA   -89.01mA
[POWER Clamp]
|   Voltage   I(typ)   I(min)   I(max)
-3.3V     262.4mA    183.1mA    340.6mA
-1.505V   52.85mA    33.12mA    76.03mA
-1.44V    47.18mA    29.34mA    68.36mA
-1.245V   31.62mA    19.16mA    47.07mA
-1.175V   26.63mA    15.95mA    40.12mA
-1.07V    19.79mA    11.63mA    30.48mA
-935mV    12.27mA    7.003mA    19.65mA
-785mV    5.873mA    3.236mA    10.14mA
-630mV    1.332mA    997uA      2.826mA
-565mV    412.5uA    348.1uA    1.013mA
-515mV    136.2uA    138.7uA    344.2uA
6.595V    0A         0A         0A
[Ramp]
R_load = 50.00Ohm
|   typ   min   max
dV/dt_r   1.189V/332.225ps 917.146mV/636.428ps   1.403V/202.229ps
dV/dt_f   1.254V/367.563ps 945.049mV/623.043ps   1.494V/239.336ps
[Falling Waveform]
V_fixture = 3.300V
V_fixture_min = 3.135V
V_fixture_max = 3.465V
R_fixture = 50.00Ohm
|   Time   V(typ)   V(min)   V(max)
0s        3.3V       3.135V     3.465V
680ps     3.34V      3.135V     3.509V
950ps     3.351V     3.14V      1.984V
1.06ns    3.152V     3.144V     1.361V
1.28ns    2.389V     3.168V     1.045V
1.58ns    1.485V     3.176V     989.3mV
1.9ns     1.272V     2.945V     978mV
2.49ns    1.218V     2.004V     975mV
2.92ns    1.212V     1.674V     975.2mV
6ns       1.211V     1.56V      974.6mV
[Rising Waveform]
V_fixture = 3.300V
V_fixture_min = 3.135V
V_fixture_max = 3.465V
R_fixture = 50.00Ohm
|   Time   V(typ)   V(min)   V(max)
0s        1.211V     1.56V      974.6mV
690ps     1.206V     1.561V     1.064V
750ps     1.204V     1.561V     1.389V
890ps     1.242V     1.56V      3.039V
1.06ns    1.8V       1.554V     3.428V
1.24ns    2.948V     1.548V     3.453V
1.47ns    3.268V     1.618V     3.462V
1.9ns     3.297V     2.816V     3.464V
2.2ns     3.299V     3.069V     3.465V
6ns       3.3V       3.135V     3.465V
[Rising Waveform]
V_fixture = 0.000V
V_fixture_min = 0.000V
V_fixture_max = 0.000V
R_fixture = 50.00Ohm
|   Time   V(typ)   V(min)   V(max)
0s        46.68nV    388.3nV    27.08nV
780ps     -3.636mV   137.8uV    -31.58mV
1.07ns    -57.93mV   579.9uV    1.849V
1.18ns    14.16mV    291.5uV    2.134V
1.35ns    686.3mV    -5.606mV   2.271V
1.65ns    1.647V     -31.57mV   2.322V
2.02ns    1.919V     -34.15mV   2.335V
2.76ns    1.976V     1.016V     2.339V
3.23ns    1.979V     1.372V     2.339V
6ns       1.982V     1.529V     2.339V
[Falling Waveform]
V_fixture = 0.000V
V_fixture_min = 0.000V
V_fixture_max = 0.000V
R_fixture = 50.00Ohm
|   Time   V(typ)   V(min)   V(max)
0s        1.982V     1.529V     2.339V
420ps     1.989V     1.527V     2.248V
470ps     1.978V     1.529V     2.02V
630ps     1.66V      1.541V     659.8mV
780ps     678.1mV    1.535V     162.2mV
890ps     324.1mV    1.496V     34.24mV
1.14ns    55.72mV    1.2V       8.351mV
1.43ns    12.34mV    291.9mV    3.564mV
1.71ns    5.619mV    80.52mV    1.035mV
6ns       46.68nV    388.3nV    27.08nV
